VERSION 5.7 ;
  NOWIREEXTENSIONATPIN ON ;
  DIVIDERCHAR "/" ;
  BUSBITCHARS "[]" ;
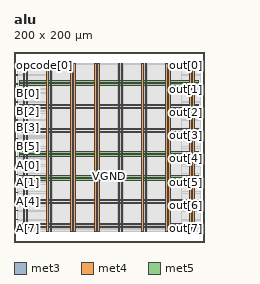
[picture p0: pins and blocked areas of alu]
MACRO alu
  CLASS BLOCK ;
  FOREIGN alu ;
  ORIGIN 0.000 0.000 ;
  SIZE 200.000 BY 200.000 ;
  PIN A[0]
    DIRECTION INPUT ;
    USE SIGNAL ;
    ANTENNAGATEAREA 0.247500 ;
    PORT
      LAYER met3 ;
        RECT 0.000 80.280 4.000 80.880 ;
    END
  END A[0]
  PIN A[1]
    DIRECTION INPUT ;
    USE SIGNAL ;
    ANTENNAGATEAREA 0.426000 ;
    PORT
      LAYER met3 ;
        RECT 0.000 70.760 4.000 71.360 ;
    END
  END A[1]
  PIN A[2]
    DIRECTION INPUT ;
    USE SIGNAL ;
    ANTENNAGATEAREA 0.426000 ;
    PORT
      LAYER met3 ;
        RECT 0.000 61.240 4.000 61.840 ;
    END
  END A[2]
  PIN A[3]
    DIRECTION INPUT ;
    USE SIGNAL ;
    ANTENNAGATEAREA 0.495000 ;
    PORT
      LAYER met3 ;
        RECT 0.000 51.720 4.000 52.320 ;
    END
  END A[3]
  PIN A[4]
    DIRECTION INPUT ;
    USE SIGNAL ;
    ANTENNAGATEAREA 0.495000 ;
    PORT
      LAYER met3 ;
        RECT 0.000 42.200 4.000 42.800 ;
    END
  END A[4]
  PIN A[5]
    DIRECTION INPUT ;
    USE SIGNAL ;
    ANTENNAGATEAREA 0.213000 ;
    PORT
      LAYER met3 ;
        RECT 0.000 32.680 4.000 33.280 ;
    END
  END A[5]
  PIN A[6]
    DIRECTION INPUT ;
    USE SIGNAL ;
    ANTENNAGATEAREA 0.742500 ;
    PORT
      LAYER met3 ;
        RECT 0.000 23.160 4.000 23.760 ;
    END
  END A[6]
  PIN A[7]
    DIRECTION INPUT ;
    USE SIGNAL ;
    ANTENNAGATEAREA 0.247500 ;
    PORT
      LAYER met3 ;
        RECT 0.000 13.640 4.000 14.240 ;
    END
  END A[7]
  PIN B[0]
    DIRECTION INPUT ;
    USE SIGNAL ;
    ANTENNAGATEAREA 0.495000 ;
    PORT
      LAYER met3 ;
        RECT 0.000 156.440 4.000 157.040 ;
    END
  END B[0]
  PIN B[1]
    DIRECTION INPUT ;
    USE SIGNAL ;
    ANTENNAGATEAREA 0.990000 ;
    PORT
      LAYER met3 ;
        RECT 0.000 146.920 4.000 147.520 ;
    END
  END B[1]
  PIN B[2]
    DIRECTION INPUT ;
    USE SIGNAL ;
    ANTENNAGATEAREA 0.247500 ;
    PORT
      LAYER met3 ;
        RECT 0.000 137.400 4.000 138.000 ;
    END
  END B[2]
  PIN B[3]
    DIRECTION INPUT ;
    USE SIGNAL ;
    ANTENNAGATEAREA 0.247500 ;
    PORT
      LAYER met3 ;
        RECT 0.000 127.880 4.000 128.480 ;
    END
  END B[3]
  PIN B[4]
    DIRECTION INPUT ;
    USE SIGNAL ;
    ANTENNAGATEAREA 0.213000 ;
    PORT
      LAYER met3 ;
        RECT 0.000 118.360 4.000 118.960 ;
    END
  END B[4]
  PIN B[5]
    DIRECTION INPUT ;
    USE SIGNAL ;
    ANTENNAGATEAREA 0.742500 ;
    PORT
      LAYER met3 ;
        RECT 0.000 108.840 4.000 109.440 ;
    END
  END B[5]
  PIN B[6]
    DIRECTION INPUT ;
    USE SIGNAL ;
    ANTENNAGATEAREA 0.426000 ;
    PORT
      LAYER met3 ;
        RECT 0.000 99.320 4.000 99.920 ;
    END
  END B[6]
  PIN B[7]
    DIRECTION INPUT ;
    USE SIGNAL ;
    ANTENNAGATEAREA 0.213000 ;
    PORT
      LAYER met3 ;
        RECT 0.000 89.800 4.000 90.400 ;
    END
  END B[7]
  PIN VGND
    DIRECTION INOUT ;
    USE GROUND ;
    PORT
      LAYER met4 ;
        RECT 13.020 10.640 14.620 187.920 ;
    END
    PORT
      LAYER met4 ;
        RECT 38.020 10.640 39.620 187.920 ;
    END
    PORT
      LAYER met4 ;
        RECT 63.020 10.640 64.620 187.920 ;
    END
    PORT
      LAYER met4 ;
        RECT 88.020 10.640 89.620 187.920 ;
    END
    PORT
      LAYER met4 ;
        RECT 113.020 10.640 114.620 187.920 ;
    END
    PORT
      LAYER met4 ;
        RECT 138.020 10.640 139.620 187.920 ;
    END
    PORT
      LAYER met4 ;
        RECT 163.020 10.640 164.620 187.920 ;
    END
    PORT
      LAYER met4 ;
        RECT 188.020 10.640 189.620 187.920 ;
    END
    PORT
      LAYER met5 ;
        RECT 5.280 18.380 194.360 19.980 ;
    END
    PORT
      LAYER met5 ;
        RECT 5.280 43.380 194.360 44.980 ;
    END
    PORT
      LAYER met5 ;
        RECT 5.280 68.380 194.360 69.980 ;
    END
    PORT
      LAYER met5 ;
        RECT 5.280 93.380 194.360 94.980 ;
    END
    PORT
      LAYER met5 ;
        RECT 5.280 118.380 194.360 119.980 ;
    END
    PORT
      LAYER met5 ;
        RECT 5.280 143.380 194.360 144.980 ;
    END
    PORT
      LAYER met5 ;
        RECT 5.280 168.380 194.360 169.980 ;
    END
  END VGND
  PIN VPWR
    DIRECTION INOUT ;
    USE POWER ;
    PORT
      LAYER met4 ;
        RECT 9.720 10.640 11.320 187.920 ;
    END
    PORT
      LAYER met4 ;
        RECT 34.720 10.640 36.320 187.920 ;
    END
    PORT
      LAYER met4 ;
        RECT 59.720 10.640 61.320 187.920 ;
    END
    PORT
      LAYER met4 ;
        RECT 84.720 10.640 86.320 187.920 ;
    END
    PORT
      LAYER met4 ;
        RECT 109.720 10.640 111.320 187.920 ;
    END
    PORT
      LAYER met4 ;
        RECT 134.720 10.640 136.320 187.920 ;
    END
    PORT
      LAYER met4 ;
        RECT 159.720 10.640 161.320 187.920 ;
    END
    PORT
      LAYER met4 ;
        RECT 184.720 10.640 186.320 187.920 ;
    END
    PORT
      LAYER met5 ;
        RECT 5.280 15.080 194.360 16.680 ;
    END
    PORT
      LAYER met5 ;
        RECT 5.280 40.080 194.360 41.680 ;
    END
    PORT
      LAYER met5 ;
        RECT 5.280 65.080 194.360 66.680 ;
    END
    PORT
      LAYER met5 ;
        RECT 5.280 90.080 194.360 91.680 ;
    END
    PORT
      LAYER met5 ;
        RECT 5.280 115.080 194.360 116.680 ;
    END
    PORT
      LAYER met5 ;
        RECT 5.280 140.080 194.360 141.680 ;
    END
    PORT
      LAYER met5 ;
        RECT 5.280 165.080 194.360 166.680 ;
    END
  END VPWR
  PIN opcode[0]
    DIRECTION INPUT ;
    USE SIGNAL ;
    ANTENNAGATEAREA 0.247500 ;
    PORT
      LAYER met3 ;
        RECT 0.000 185.000 4.000 185.600 ;
    END
  END opcode[0]
  PIN opcode[1]
    DIRECTION INPUT ;
    USE SIGNAL ;
    ANTENNAGATEAREA 0.247500 ;
    PORT
      LAYER met3 ;
        RECT 0.000 175.480 4.000 176.080 ;
    END
  END opcode[1]
  PIN opcode[2]
    DIRECTION INPUT ;
    USE SIGNAL ;
    ANTENNAGATEAREA 0.426000 ;
    PORT
      LAYER met3 ;
        RECT 0.000 165.960 4.000 166.560 ;
    END
  END opcode[2]
  PIN out[0]
    DIRECTION OUTPUT ;
    USE SIGNAL ;
    ANTENNADIFFAREA 0.445500 ;
    PORT
      LAYER met3 ;
        RECT 196.000 185.000 200.000 185.600 ;
    END
  END out[0]
  PIN out[1]
    DIRECTION OUTPUT ;
    USE SIGNAL ;
    ANTENNADIFFAREA 0.445500 ;
    PORT
      LAYER met3 ;
        RECT 196.000 160.520 200.000 161.120 ;
    END
  END out[1]
  PIN out[2]
    DIRECTION OUTPUT ;
    USE SIGNAL ;
    ANTENNADIFFAREA 0.445500 ;
    PORT
      LAYER met3 ;
        RECT 196.000 136.040 200.000 136.640 ;
    END
  END out[2]
  PIN out[3]
    DIRECTION OUTPUT ;
    USE SIGNAL ;
    ANTENNADIFFAREA 0.445500 ;
    PORT
      LAYER met3 ;
        RECT 196.000 111.560 200.000 112.160 ;
    END
  END out[3]
  PIN out[4]
    DIRECTION OUTPUT ;
    USE SIGNAL ;
    ANTENNADIFFAREA 0.445500 ;
    PORT
      LAYER met3 ;
        RECT 196.000 87.080 200.000 87.680 ;
    END
  END out[4]
  PIN out[5]
    DIRECTION OUTPUT ;
    USE SIGNAL ;
    ANTENNADIFFAREA 0.445500 ;
    PORT
      LAYER met3 ;
        RECT 196.000 62.600 200.000 63.200 ;
    END
  END out[5]
  PIN out[6]
    DIRECTION OUTPUT ;
    USE SIGNAL ;
    ANTENNADIFFAREA 1.336500 ;
    PORT
      LAYER met3 ;
        RECT 196.000 38.120 200.000 38.720 ;
    END
  END out[6]
  PIN out[7]
    DIRECTION OUTPUT ;
    USE SIGNAL ;
    ANTENNADIFFAREA 1.782000 ;
    PORT
      LAYER met3 ;
        RECT 196.000 13.640 200.000 14.240 ;
    END
  END out[7]
  OBS
      LAYER nwell ;
        RECT 5.330 10.795 194.310 187.870 ;
      LAYER li1 ;
        RECT 5.520 10.795 194.120 187.765 ;
      LAYER met1 ;
        RECT 4.210 10.640 194.120 187.920 ;
      LAYER met2 ;
        RECT 4.230 10.695 192.190 187.865 ;
      LAYER met3 ;
        RECT 3.990 186.000 196.000 187.845 ;
        RECT 4.400 184.600 195.600 186.000 ;
        RECT 3.990 176.480 196.000 184.600 ;
        RECT 4.400 175.080 196.000 176.480 ;
        RECT 3.990 166.960 196.000 175.080 ;
        RECT 4.400 165.560 196.000 166.960 ;
        RECT 3.990 161.520 196.000 165.560 ;
        RECT 3.990 160.120 195.600 161.520 ;
        RECT 3.990 157.440 196.000 160.120 ;
        RECT 4.400 156.040 196.000 157.440 ;
        RECT 3.990 147.920 196.000 156.040 ;
        RECT 4.400 146.520 196.000 147.920 ;
        RECT 3.990 138.400 196.000 146.520 ;
        RECT 4.400 137.040 196.000 138.400 ;
        RECT 4.400 137.000 195.600 137.040 ;
        RECT 3.990 135.640 195.600 137.000 ;
        RECT 3.990 128.880 196.000 135.640 ;
        RECT 4.400 127.480 196.000 128.880 ;
        RECT 3.990 119.360 196.000 127.480 ;
        RECT 4.400 117.960 196.000 119.360 ;
        RECT 3.990 112.560 196.000 117.960 ;
        RECT 3.990 111.160 195.600 112.560 ;
        RECT 3.990 109.840 196.000 111.160 ;
        RECT 4.400 108.440 196.000 109.840 ;
        RECT 3.990 100.320 196.000 108.440 ;
        RECT 4.400 98.920 196.000 100.320 ;
        RECT 3.990 90.800 196.000 98.920 ;
        RECT 4.400 89.400 196.000 90.800 ;
        RECT 3.990 88.080 196.000 89.400 ;
        RECT 3.990 86.680 195.600 88.080 ;
        RECT 3.990 81.280 196.000 86.680 ;
        RECT 4.400 79.880 196.000 81.280 ;
        RECT 3.990 71.760 196.000 79.880 ;
        RECT 4.400 70.360 196.000 71.760 ;
        RECT 3.990 63.600 196.000 70.360 ;
        RECT 3.990 62.240 195.600 63.600 ;
        RECT 4.400 62.200 195.600 62.240 ;
        RECT 4.400 60.840 196.000 62.200 ;
        RECT 3.990 52.720 196.000 60.840 ;
        RECT 4.400 51.320 196.000 52.720 ;
        RECT 3.990 43.200 196.000 51.320 ;
        RECT 4.400 41.800 196.000 43.200 ;
        RECT 3.990 39.120 196.000 41.800 ;
        RECT 3.990 37.720 195.600 39.120 ;
        RECT 3.990 33.680 196.000 37.720 ;
        RECT 4.400 32.280 196.000 33.680 ;
        RECT 3.990 24.160 196.000 32.280 ;
        RECT 4.400 22.760 196.000 24.160 ;
        RECT 3.990 14.640 196.000 22.760 ;
        RECT 4.400 13.240 195.600 14.640 ;
        RECT 3.990 10.715 196.000 13.240 ;
      LAYER met4 ;
        RECT 37.095 17.175 37.620 186.825 ;
        RECT 40.020 17.175 59.320 186.825 ;
        RECT 61.720 17.175 62.620 186.825 ;
        RECT 65.020 17.175 84.320 186.825 ;
        RECT 86.720 17.175 87.620 186.825 ;
        RECT 90.020 17.175 109.320 186.825 ;
        RECT 111.720 17.175 112.620 186.825 ;
        RECT 115.020 17.175 134.320 186.825 ;
        RECT 136.720 17.175 137.620 186.825 ;
        RECT 140.020 17.175 159.320 186.825 ;
        RECT 161.720 17.175 162.620 186.825 ;
        RECT 165.020 17.175 176.345 186.825 ;
  END
END alu
END LIBRARY

